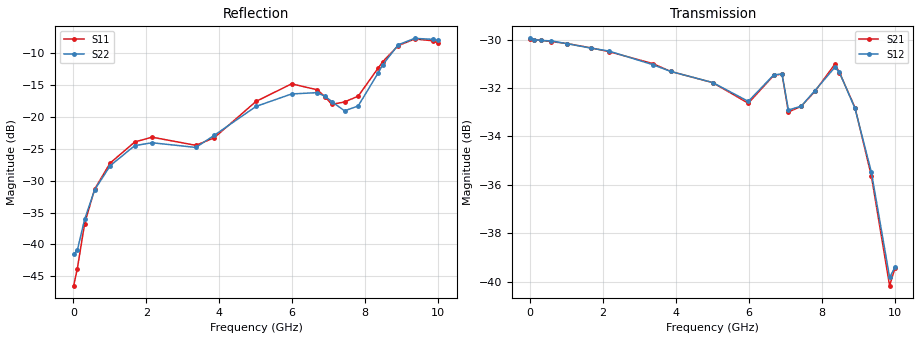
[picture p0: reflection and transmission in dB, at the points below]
! Device ID: PE43705
! Serial: 1
! Insertion: A
! Impedance: 50 ohm
! Temp: 25C
! VDD: 3.400V
! Attenuation Step: 29.00dB
#  Hz  S  RI  R  50
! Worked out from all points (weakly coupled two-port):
!   401 points, 10 MHz to 10.01 GHz, reference 50 ohm
!   highest |S21| = -29.97 dB at 10 MHz (marker M1); lowest = -40.2 dB at 9.86 GHz (marker M2)
!   lowest |S11| = -46.5 dB at 10 MHz (marker M3), VSWR 1.01, Z = 49.5 + j0.0474 ohm
!   |S11| at or under -10 dB: start of sweep to 8.672 GHz
!   |S22| runs from -41.7 to -7.5 dB; largest |S21 - S12| = 0.00067
!   S11 on the Smith chart (normalised r, x): 10 MHz: 0.99, +0.00; 7.435 GHz: 0.82, +0.16; 8.485 GHz: 0.84, +0.49; 9.36 GHz: 0.55, +0.49; 10.01 GHz: 0.49, +0.27
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1e7  -0.00472 0.000479  0.0317 -7.68e-05  0.0318 -5.91e-05  -0.00833 0.000487
1.1e8  -0.00443 0.00469  0.0316 -0.000893  0.0316 -0.000872  -0.00775 0.00461
3.1e8  -0.00678 0.0129  0.0314 -0.00243  0.0314 -0.00242  -0.00972 0.0124
5.85e8  -0.0147 0.0229  0.031 -0.00446  0.0311 -0.00443  -0.0163 0.0213
1.01e9  -0.0337 0.0276  0.0301 -0.00754  0.0301 -0.00747  -0.0328 0.0254
1.685e9  -0.0613 0.0177  0.028 -0.0118  0.028 -0.0117  -0.057 0.0178
2.16e9  -0.0694 0.00428  0.0261 -0.0145  0.0262 -0.0145  -0.0624 0.00766
3.36e9  -0.0598 0.00495  0.0202 -0.0197  0.0201 -0.0196  -0.0565 0.0121
3.86e9  -0.0628 0.0279  0.0176 -0.0207  0.0176 -0.0207  -0.0666 0.0268
5.01e9  -0.0991 0.0884  0.0129 -0.0223  0.0131 -0.0222  -0.1028 0.0644
5.985e9  -0.1503 0.1034  0.00787 -0.022  0.00819 -0.0221  -0.1297 0.0792
6.685e9  -0.1415 0.0826  0.00641 -0.0259  0.00666 -0.0259  -0.1373 0.0731
6.91e9  -0.123 0.0743  0.00261 -0.0267  0.00282 -0.0267  -0.1257 0.0725
7.085e9  -0.1077 0.065  0.000792 -0.0224  0.00103 -0.0226  -0.1078 0.0769
7.435e9  -0.089 0.0968  0.00236 -0.0229  0.00244 -0.0229  -0.0737 0.0843
7.81e9  -0.042 0.1398  0.00226 -0.0246  0.00223 -0.0247  -0.0481 0.1124
8.36e9  -0.00845 0.2429  -0.00592 -0.0275  -0.00581 -0.0271  -0.0365 0.2197
8.485e9  -0.0147 0.2723  -0.00866 -0.0256  -0.00813 -0.0258  -0.0441 0.2541
8.91e9  -0.0714 0.3574  -0.0123 -0.0193  -0.0123 -0.0192  -0.1067 0.3543
9.36e9  -0.1714 0.3727  -0.0107 -0.0126  -0.0108 -0.0129  -0.1993 0.3641
9.86e9  -0.2785 0.2835  -0.00367 -0.0091  -0.00369 -0.00952  -0.3167 0.257
1.001e10  -0.3025 0.2362  -0.00136 -0.0106  -0.000707 -0.0107  -0.3469 0.1979
